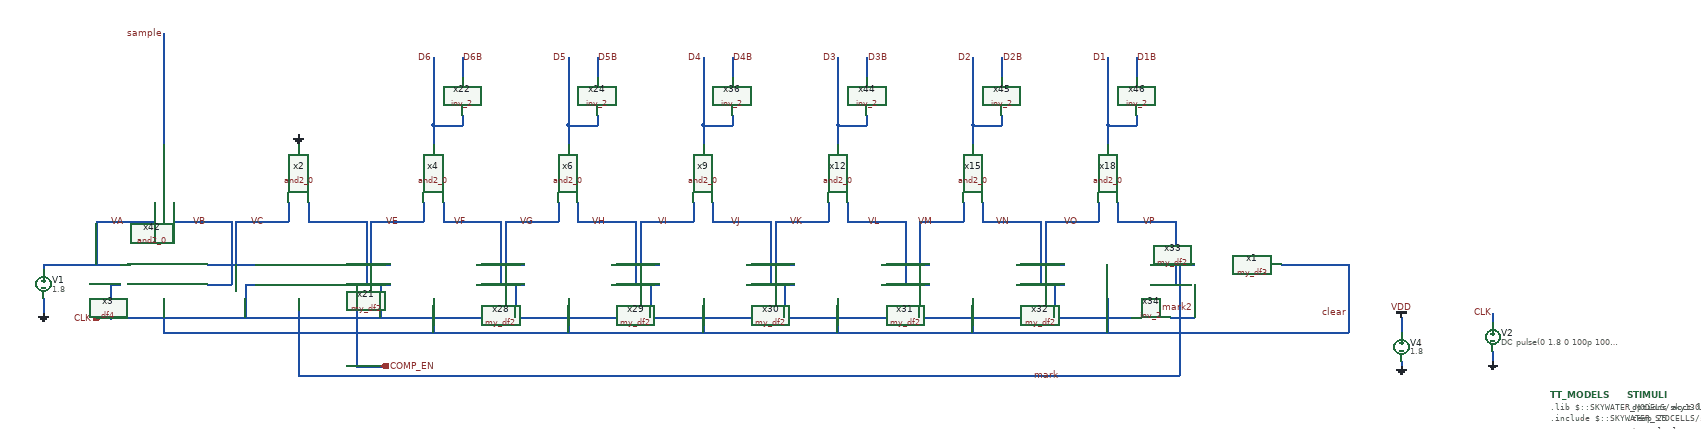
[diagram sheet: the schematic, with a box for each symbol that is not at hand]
v {xschem version=3.0.0 file_version=1.2 }
G {}
K {}
V {}
S {}
E {}
N 90 -400 90 -370 {
lab=GND}
N 90 -470 90 -460 {
lab=VA}
N 150 -470 250 -470 {
lab=VA}
N 200 -560 200 -470 {
lab=VA}
N 200 -560 320 -560 {
lab=VA}
N 320 -600 320 -560 {
lab=VA}
N 360 -600 360 -560 {
lab=VB}
N 360 -560 480 -560 {
lab=VB}
N 90 -470 150 -470 {
lab=VA}
N 600 -600 600 -560 {
lab=VC}
N 640 -600 640 -560 {
lab=COMP_EN}
N 640 -560 760 -560 {
lab=COMP_EN}
N 490 -560 600 -560 {
lab=VC}
N 880 -600 880 -560 {
lab=VE}
N 920 -600 920 -560 {
lab=VF}
N 920 -560 1040 -560 {
lab=VF}
N 770 -560 880 -560 {
lab=VE}
N 900 -900 900 -760 {
lab=D6}
N 900 -760 960 -760 {
lab=D6}
N 960 -780 960 -770 {
lab=D6}
N 1160 -600 1160 -560 {
lab=VG}
N 1200 -600 1200 -560 {
lab=VH}
N 1200 -560 1320 -560 {
lab=VH}
N 1050 -560 1160 -560 {
lab=VG}
N 1180 -900 1180 -760 {
lab=D5}
N 1180 -760 1240 -760 {
lab=D5}
N 1240 -780 1240 -770 {
lab=D5}
N 1240 -900 1240 -860 {
lab=D5B}
N 1440 -600 1440 -560 {
lab=VI}
N 1480 -600 1480 -560 {
lab=VJ}
N 1480 -560 1600 -560 {
lab=VJ}
N 1330 -560 1440 -560 {
lab=VI}
N 1460 -900 1460 -760 {
lab=D4}
N 1460 -760 1520 -760 {
lab=D4}
N 1520 -780 1520 -770 {
lab=D4}
N 1520 -900 1520 -860 {
lab=D4B}
N 1720 -600 1720 -560 {
lab=VK}
N 1760 -600 1760 -560 {
lab=VL}
N 1760 -560 1880 -560 {
lab=VL}
N 1610 -560 1720 -560 {
lab=VK}
N 1740 -900 1740 -760 {
lab=D3}
N 1740 -760 1800 -760 {
lab=D3}
N 1800 -780 1800 -770 {
lab=D3}
N 1800 -900 1800 -860 {
lab=D3B}
N 2040 -600 2040 -560 {
lab=VN}
N 2040 -560 2160 -560 {
lab=VN}
N 2020 -900 2020 -760 {
lab=D2}
N 2020 -760 2080 -760 {
lab=D2}
N 2080 -780 2080 -770 {
lab=D2}
N 2080 -900 2080 -860 {
lab=D2B}
N 2280 -600 2280 -560 {
lab=VO}
N 2320 -600 2320 -560 {
lab=VP}
N 2320 -560 2440 -560 {
lab=VP}
N 2170 -560 2280 -560 {
lab=VO}
N 2300 -900 2300 -760 {
lab=D1}
N 2300 -760 2360 -760 {
lab=D1}
N 2360 -780 2360 -770 {
lab=D1}
N 2360 -900 2360 -860 {
lab=D1B}
N 340 -950 340 -760 {
lab=sample}
N 1520 -770 1520 -760 {
lab=D4}
N 1240 -770 1240 -760 {
lab=D5}
N 960 -770 960 -760 {
lab=D6}
N 1800 -770 1800 -760 {
lab=D3}
N 2080 -770 2080 -760 {
lab=D2}
N 2360 -770 2360 -760 {
lab=D1}
N 2300 -760 2300 -720 {
lab=D1}
N 2020 -760 2020 -720 {
lab=D2}
N 1740 -760 1740 -720 {
lab=D3}
N 1460 -760 1460 -720 {
lab=D4}
N 1180 -760 1180 -720 {
lab=D5}
N 900 -760 900 -720 {
lab=D6}
N 340 -760 340 -720 {
lab=sample}
N 620 -740 620 -720 {
lab=GND}
N 430 -470 530 -470 {
lab=VC}
N 710 -470 810 -470 {
lab=VE}
N 990 -470 1090 -470 {
lab=VG}
N 1270 -470 1370 -470 {
lab=VI}
N 1550 -470 1650 -470 {
lab=VK}
N 2110 -470 2210 -470 {
lab=VO}
N 480 -560 480 -430 {
lab=VB}
N 430 -430 480 -430 {
lab=VB}
N 710 -430 760 -430 {
lab=COMP_EN}
N 760 -560 760 -430 {
lab=COMP_EN}
N 1040 -560 1040 -430 {
lab=VF}
N 990 -430 1040 -430 {
lab=VF}
N 1320 -560 1320 -430 {
lab=VH}
N 1600 -560 1600 -430 {
lab=VJ}
N 1270 -430 1320 -430 {
lab=VH}
N 1550 -430 1600 -430 {
lab=VJ}
N 1880 -560 1880 -430 {
lab=VL}
N 1830 -430 1880 -430 {
lab=VL}
N 2160 -560 2160 -430 {
lab=VN}
N 2440 -560 2440 -430 {
lab=VP}
N 2110 -430 2160 -430 {
lab=VN}
N 2390 -430 2440 -430 {
lab=VP}
N 490 -560 490 -470 {
lab=VC}
N 770 -560 770 -470 {
lab=VE}
N 1050 -560 1050 -470 {
lab=VG}
N 2170 -560 2170 -470 {
lab=VO}
N 1610 -560 1610 -470 {
lab=VK}
N 1330 -560 1330 -470 {
lab=VI}
N 200 -360 230 -360 {
lab=CLK}
N 230 -430 250 -430 {
lab=CLK}
N 230 -430 230 -360 {
lab=CLK}
N 510 -430 530 -430 {
lab=CLK}
N 510 -430 510 -360 {
lab=CLK}
N 790 -430 810 -430 {
lab=CLK}
N 790 -430 790 -360 {
lab=CLK}
N 1070 -430 1090 -430 {
lab=CLK}
N 1070 -430 1070 -360 {
lab=CLK}
N 1350 -430 1370 -430 {
lab=CLK}
N 1350 -430 1350 -360 {
lab=CLK}
N 1630 -430 1650 -430 {
lab=CLK}
N 1630 -430 1630 -360 {
lab=CLK}
N 1910 -430 1930 -430 {
lab=CLK}
N 1910 -430 1910 -360 {
lab=CLK}
N 2190 -430 2210 -430 {
lab=CLK}
N 2190 -430 2190 -360 {
lab=CLK}
N 230 -360 2350 -360 {
lab=CLK}
N 340 -400 340 -380 {
lab=clear}
N 340 -380 340 -330 {
lab=clear}
N 340 -330 2800 -330 {
lab=clear}
N 900 -400 900 -330 {
lab=clear}
N 1180 -400 1180 -330 {
lab=clear}
N 1460 -400 1460 -330 {
lab=clear}
N 1740 -400 1740 -330 {
lab=clear}
N 2020 -400 2020 -330 {
lab=clear}
N 2300 -400 2300 -330 {
lab=clear}
N 2480 -430 2480 -360 {
lab=mark2}
N 2430 -360 2480 -360 {
lab=mark2}
N 2660 -470 2800 -470 {
lab=clear}
N 740 -430 740 -260 {
lab=COMP_EN}
N 740 -260 800 -260 {
lab=COMP_EN}
N 2390 -470 2480 -470 {
lab=mark}
N 2450 -470 2450 -240 {
lab=mark}
N 620 -240 2450 -240 {
lab=mark}
N 620 -400 620 -240 {
lab=mark}
N 2800 -470 2800 -330 {
lab=clear}
N 960 -900 960 -860 {
lab=D6B}
N 3100 -290 3100 -270 {
lab=GND}
N 3100 -370 3100 -350 {
lab=CLK}
N 2910 -360 2910 -330 {
lab=VDD}
N 2910 -270 2910 -260 {
lab=GND}
N 1830 -470 1930 -470 {
lab=VM}
N 1910 -560 1910 -470 {
lab=VM}
N 1910 -560 2000 -560 {
lab=VM}
N 2000 -600 2000 -560 {
lab=VM}
C {vsource.sym} 90 -430 0 0 {name=V1 value=1.8}
C {gnd.sym} 90 -370 0 0 {name=l1 lab=GND}
C {lab_pin.sym} 900 -900 1 0 {name=l9 lab=D6}
C {lab_pin.sym} 1180 -900 1 0 {name=l11 lab=D5}
C {lab_pin.sym} 1460 -900 1 0 {name=l12 lab=D4}
C {lab_pin.sym} 1740 -900 1 0 {name=l13 lab=D3}
C {lab_pin.sym} 2020 -900 1 0 {name=l14 lab=D2}
C {lab_pin.sym} 2300 -900 1 0 {name=l15 lab=D1}
C {xschem_sky130/sky130_stdcells/inv_2.sym} 960 -820 3 0 {name=x22 VGND=GND VNB=GND VPB=VDD VPWR=VDD prefix=sky130_fd_sc_hd__ }
C {xschem_sky130/sky130_stdcells/inv_2.sym} 1240 -820 3 0 {name=x24 VGND=GND VNB=GND VPB=VDD VPWR=VDD prefix=sky130_fd_sc_hd__ }
C {xschem_sky130/sky130_stdcells/inv_2.sym} 1520 -820 3 0 {name=x36 VGND=GND VNB=GND VPB=VDD VPWR=VDD prefix=sky130_fd_sc_hd__ }
C {xschem_sky130/sky130_stdcells/inv_2.sym} 1800 -820 3 0 {name=x44 VGND=GND VNB=GND VPB=VDD VPWR=VDD prefix=sky130_fd_sc_hd__ }
C {xschem_sky130/sky130_stdcells/inv_2.sym} 2080 -820 3 0 {name=x45 VGND=GND VNB=GND VPB=VDD VPWR=VDD prefix=sky130_fd_sc_hd__ }
C {xschem_sky130/sky130_stdcells/inv_2.sym} 2360 -820 3 0 {name=x46 VGND=GND VNB=GND VPB=VDD VPWR=VDD prefix=sky130_fd_sc_hd__ }
C {xschem_sky130/sky130_stdcells/and2_0.sym} 340 -660 3 0 {name=x42 VGND=GND VNB=GND VPB=VDD VPWR=VDD prefix=sky130_fd_sc_hd__ }
C {xschem_sky130/sky130_stdcells/and2_0.sym} 620 -660 3 0 {name=x2 VGND=GND VNB=GND VPB=VDD VPWR=VDD prefix=sky130_fd_sc_hd__ }
C {xschem_sky130/sky130_stdcells/and2_0.sym} 900 -660 3 0 {name=x4 VGND=GND VNB=GND VPB=VDD VPWR=VDD prefix=sky130_fd_sc_hd__ }
C {xschem_sky130/sky130_stdcells/and2_0.sym} 1180 -660 3 0 {name=x6 VGND=GND VNB=GND VPB=VDD VPWR=VDD prefix=sky130_fd_sc_hd__ }
C {xschem_sky130/sky130_stdcells/and2_0.sym} 1460 -660 3 0 {name=x9 VGND=GND VNB=GND VPB=VDD VPWR=VDD prefix=sky130_fd_sc_hd__ }
C {xschem_sky130/sky130_stdcells/and2_0.sym} 1740 -660 3 0 {name=x12 VGND=GND VNB=GND VPB=VDD VPWR=VDD prefix=sky130_fd_sc_hd__ }
C {xschem_sky130/sky130_stdcells/and2_0.sym} 2020 -660 3 0 {name=x15 VGND=GND VNB=GND VPB=VDD VPWR=VDD prefix=sky130_fd_sc_hd__ }
C {xschem_sky130/sky130_stdcells/and2_0.sym} 2300 -660 3 0 {name=x18 VGND=GND VNB=GND VPB=VDD VPWR=VDD prefix=sky130_fd_sc_hd__ }
C {my_df2.sym} 680 -450 0 0 {name=x21}
C {my_df2.sym} 960 -450 0 0 {name=x28}
C {my_df2.sym} 1240 -450 0 0 {name=x29}
C {my_df2.sym} 1520 -450 0 0 {name=x30}
C {my_df2.sym} 1800 -450 0 0 {name=x31}
C {my_df2.sym} 2080 -450 0 0 {name=x32}
C {my_df2.sym} 2360 -450 0 0 {name=x33}
C {ipin.sym} 210 -360 0 0 {name=p2 lab=CLK}
C {xschem_sky130/sky130_stdcells/inv_2.sym} 2390 -360 0 0 {name=x34 VGND=GND VNB=GND VPB=VDD VPWR=VDD prefix=sky130_fd_sc_hd__ }
C {opin.sym} 790 -260 0 0 {name=p1 lab=COMP_EN}
C {lab_wire.sym} 960 -900 0 1 {name=l8 sig_type=std_logic lab=D6B}
C {lab_wire.sym} 1240 -900 0 1 {name=l30 sig_type=std_logic lab=D5B}
C {lab_wire.sym} 1520 -900 0 1 {name=l31 sig_type=std_logic lab=D4B}
C {lab_wire.sym} 1800 -900 0 1 {name=l32 sig_type=std_logic lab=D3B}
C {lab_wire.sym} 2080 -900 0 1 {name=l33 sig_type=std_logic lab=D2B}
C {lab_wire.sym} 2360 -900 0 1 {name=l34 sig_type=std_logic lab=D1B}
C {lab_wire.sym} 260 -560 0 0 {name=l35 sig_type=std_logic lab=VA}
C {lab_wire.sym} 430 -560 0 0 {name=l36 sig_type=std_logic lab=VB}
C {lab_wire.sym} 550 -560 0 0 {name=l37 sig_type=std_logic lab=VC}
C {lab_wire.sym} 830 -560 0 0 {name=l39 sig_type=std_logic lab=VE}
C {lab_wire.sym} 970 -560 0 0 {name=l40 sig_type=std_logic lab=VF}
C {lab_wire.sym} 1110 -560 0 0 {name=l41 sig_type=std_logic lab=VG}
C {lab_wire.sym} 1260 -560 0 0 {name=l42 sig_type=std_logic lab=VH}
C {lab_wire.sym} 1390 -560 0 0 {name=l38 sig_type=std_logic lab=VI}
C {lab_wire.sym} 1540 -560 0 0 {name=l43 sig_type=std_logic lab=VJ
}
C {lab_wire.sym} 1670 -560 0 0 {name=l44 sig_type=std_logic lab=VK
}
C {lab_wire.sym} 1830 -560 0 0 {name=l45 sig_type=std_logic lab=VL
}
C {lab_wire.sym} 1940 -560 0 0 {name=l46 sig_type=std_logic lab=VM
}
C {lab_wire.sym} 2100 -560 0 0 {name=l47 sig_type=std_logic lab=VN
}
C {lab_wire.sym} 2240 -560 0 0 {name=l48 sig_type=std_logic lab=VO}
C {lab_wire.sym} 2400 -560 0 0 {name=l49 sig_type=std_logic lab=VP
}
C {lab_wire.sym} 2200 -240 0 0 {name=l50 sig_type=std_logic lab=mark}
C {lab_wire.sym} 2800 -370 0 0 {name=l2 sig_type=std_logic lab=clear}
C {lab_pin.sym} 340 -950 1 0 {name=l3 lab=sample
}
C {gnd.sym} 3100 -270 0 0 {name=l26 lab=GND}
C {vsource.sym} 3100 -320 0 0 {name=V2 value="DC pulse(0 1.8 0 100p 100p 11.11n 22.22n)"}
C {lab_wire.sym} 3100 -370 0 0 {name=l4 sig_type=std_logic lab=CLK}
C {code.sym} 3220 -200 0 0 {name=TT_MODELS
only_toplevel=true
format="tcleval( @value )"
value=".lib $::SKYWATER_MODELS/sky130.lib.spice tt
.include $::SKYWATER_STDCELLS/sky130_fd_sc_hd.spice
"
spice_ignore=false}
C {code.sym} 3380 -200 0 0 {name=STIMULI 
only_toplevel=true
value="
.options acct list
.temp 25

.tran 1n 1u
.control
save all
write tb_saradc2.raw
.endc
"
}
C {vsource.sym} 2910 -300 0 0 {name=V4 value=1.8
}
C {gnd.sym} 2910 -260 0 0 {name=l5 lab=GND}
C {vdd.sym} 2910 -360 0 0 {name=l6 lab=VDD}
C {lab_wire.sym} 2480 -380 0 0 {name=l16 sig_type=std_logic lab=mark2}
C {my_df3.sym} 2570 -280 0 0 {name=x1}
C {gnd.sym} 620 -740 2 0 {name=l7 lab=GND}
C {df4.sym} 370 -290 0 0 {name=x3}
